VERSION 5.7 ;
BUSBITCHARS "[]" ;
DIVIDERCHAR "/" ;

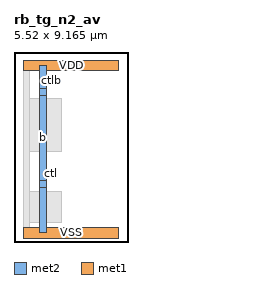
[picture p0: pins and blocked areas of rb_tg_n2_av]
MACRO rb_tg_n2_av
  CLASS BLOCK ;
  ORIGIN 0 0 ;
  FOREIGN rb_tg_n2_av 0 0 ;
  SIZE 5.520 BY 9.165 ;
  SYMMETRY X Y ;
  PIN b
    DIRECTION INOUT ;
    USE SIGNAL ;
    PORT
      LAYER met2 ;
        RECT 1.245 0.435 1.545 2.630 ;
      LAYER met2 ;
        RECT 1.230 2.630 1.560 2.960 ;
      LAYER met2 ;
        RECT 1.245 2.960 1.545 7.090 ;
      LAYER met2 ;
        RECT 1.230 7.090 1.560 7.420 ;
      LAYER met2 ;
        RECT 1.245 7.420 1.545 8.505 ;
    END
  END b
  PIN ctl
    DIRECTION INPUT ;
    USE SIGNAL ;
    PORT
      LAYER met1 ;
        RECT 1.620 3.145 1.960 3.485 ;
    END
  END ctl
  PIN ctlb
    DIRECTION INPUT ;
    USE SIGNAL ;
    PORT
      LAYER met1 ;
        RECT 1.620 7.605 1.960 7.945 ;
    END
  END ctlb
  PIN VSS
    DIRECTION INOUT ;
    USE GROUND ;
    PORT
      LAYER met1 ;
        RECT 0.460 0.185 5.060 0.685 ;
    END
  END VSS
  PIN VDD
    DIRECTION INOUT ;
    USE POWER ;
    PORT
      LAYER met1 ;
        RECT 0.460 8.255 5.060 8.755 ;
    END
  END VDD
  OBS
    LAYER met1 ;
      RECT 0.440 0.925 2.300 2.455 ;
      RECT 1.230 1.455 1.560 2.965 ;
      RECT 0.440 4.385 2.300 6.915 ;
      RECT 1.230 4.915 1.560 7.425 ;
    LAYER met2 ;
      RECT 0.440 0.435 0.770 8.755 ;
  END
END rb_tg_n2_av

END LIBRARY
